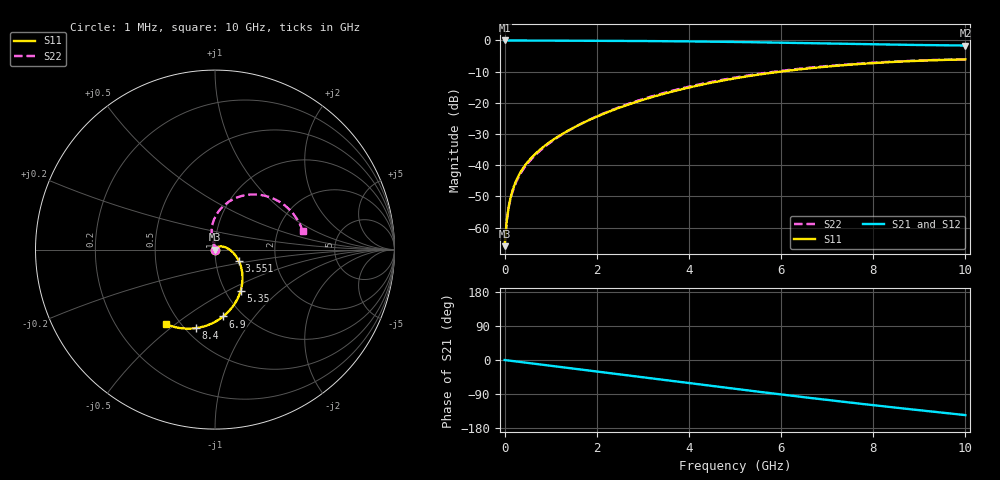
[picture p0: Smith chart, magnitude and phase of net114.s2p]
! Created with skrf 1.10.0 (http://scikit-rf.org).
# Hz S RI R 50.0
!freq ReS11 ImS11 ReS21 ImS21 ReS12 ImS12 ReS22 ImS22
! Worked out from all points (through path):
!   201 points, 1 MHz to 10 GHz, reference 50 ohm
!   highest |S21| = 0.00 dB at 1 MHz (marker M1); lowest = -1.6 dB at 10 GHz (marker M2)
!   group delay of S21, straight-line fit = 40.9 ps
!   lowest |S11| = -66.0 dB at 1 MHz (marker M3), VSWR 1.00, Z = 50.1 + j0.00207 ohm
!   |S11| at or under -10 dB: start of sweep to 5.985 GHz
!   |S22| runs from -66.0 to -6.0 dB; largest |S21 - S12| = 2.4e-11
!   S11 on the Smith chart (normalised r, x): 1 MHz: 1.00, +0.00; 3.551 GHz: 1.29, -0.16; 5.35 GHz: 1.17, -0.59; 6.9 GHz: 0.82, -0.71; 8.4 GHz: 0.56, -0.62; 10 GHz: 0.42, -0.46
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1000000  0.000503 2.07e-05  0.9995 -0.000263  0.9995 -0.000263  0.000503 2.08e-05
5.0995e7  0.000876 0.00105  0.9988 -0.0134  0.9988 -0.0134  0.000818 0.00106
1.0099e8  0.00127 0.00206  0.9981 -0.0265  0.9981 -0.0265  0.00104 0.00209
1.50985e8  0.00166 0.00306  0.9972 -0.0396  0.9972 -0.0396  0.00115 0.00313
2.0098e8  0.00208 0.00404  0.9962 -0.0527  0.9962 -0.0527  0.00118 0.00417
3.50965e8  0.00369 0.0069  0.9924 -0.0918  0.9924 -0.0918  0.000951 0.00736
5.50945e8  0.00678 0.0104  0.985 -0.1437  0.985 -0.1437  9.7e-05 0.0118
8.50915e8  0.0135 0.0146  0.969 -0.2207  0.969 -0.2207  -0.00208 0.0191
1.250875e9  0.0262 0.0177  0.9384 -0.3208  0.9384 -0.3208  -0.00613 0.0305
1.70083e9  0.0447 0.0163  0.8914 -0.4289  0.8914 -0.4289  -0.0114 0.0464
2.450755e9  0.0814 -0.00035  0.7846 -0.5937  0.7846 -0.5937  -0.0182 0.0812
3.350665e9  0.1242 -0.0474  0.6149 -0.7561  0.6149 -0.7561  -0.0149 0.1363
3.550645e9  0.1321 -0.0618  0.5721 -0.7858  0.5721 -0.7858  -0.0114 0.15
4.30057e9  0.1512 -0.126  0.3995 -0.8729  0.3995 -0.8729  0.013 0.2027
5.0005e9  0.1504 -0.1957  0.2284 -0.9177  0.2284 -0.9177  0.0531 0.2486
5.350465e9  0.1421 -0.2318  0.1422 -0.9267  0.1422 -0.9267  0.0793 0.2682
6.0004e9  0.1129 -0.2965  -0.0146 -0.9209  -0.0146 -0.9209  0.137 0.2953
6.70033e9  0.063 -0.3574  -0.173 -0.8853  -0.173 -0.8853  0.2082 0.3072
6.90031e9  0.0458 -0.3722  -0.2155 -0.8702  -0.2155 -0.8702  0.2295 0.3069
8.350165e9  -0.1025 -0.437  -0.4791 -0.7127  -0.4791 -0.7127  0.3775 0.2544
8.40016e9  -0.108 -0.4378  -0.4867 -0.7061  -0.4867 -0.7061  0.3821 0.2511
1e10  -0.275 -0.4139  -0.6827 -0.4705  -0.6827 -0.4705  0.4879 0.1054
